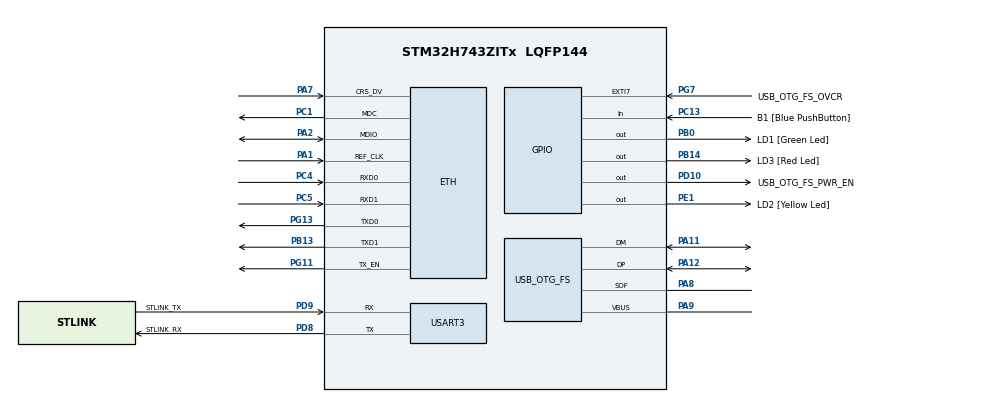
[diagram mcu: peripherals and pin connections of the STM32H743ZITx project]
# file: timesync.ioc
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Mcu.Family=STM32H7
LWIP0.BSP.STBoard=false
RCC.CortexFreq_Value=64000000
PH0-OSC_IN\ (PH0).Signal=RCC_OSC_IN
PB14.GPIO_Label=LD3 [Red Led]
PC15-OSC32_OUT\ (OSC32_OUT).Mode=LSE-External-Oscillator
RCC.PLLFRACN=0
PA11.Mode=Device_Only
PB0.GPIO_Label=LD1 [Green Led]
NVIC.TIM1_UP_IRQn=true\:0\:0\:false\:false\:true\:false\:false\:true
PC5.Mode=RMII
PC13.GPIO_Label=B1 [Blue PushButton]
PB13.Signal=ETH_TXD1
PG13.Signal=ETH_TXD0
PD9.Mode=Asynchronous
PG11.Signal=ETH_TX_EN
ProjectManager.StackSize=0x400
VP_FREERTOS_VS_CMSIS_V2.Mode=CMSIS_V2
USART3.VirtualMode-Asynchronous=VM_ASYNC
PA12.Signal=USB_OTG_FS_DP
RCC.HCLKFreq_Value=64000000
PD8.Signal=USART3_TX
PE1.Signal=GPIO_Output
NVIC.ETH_IRQn=true\:5\:0\:false\:false\:true\:true\:true\:true
RCC.HSE_VALUE=8000000
RCC.DIVM1=1
VP_SYS_VS_tim1.Mode=TIM1
PA8.Signal=USB_OTG_FS_SOF
PG13.Mode=RMII
LWIP0.BSP.solution=LAN8742
RCC.APB3Freq_Value=64000000
LWIP0.BSP.component=LAN8742
Mcu.Package=LQFP144
NVIC.TimeBase=TIM1_UP_IRQn
NVIC.TimeBaseIP=TIM1
USB_OTG_FS.VirtualMode=Device_Only
PC14-OSC32_IN\ (OSC32_IN).Mode=LSE-External-Oscillator
RCC.APB4Freq_Value=64000000
PC5.Signal=ETH_RXD1
PB13.Mode=RMII
PH0-OSC_IN\ (PH0).Mode=HSE-External-Clock-Source
PC4.Mode=RMII
RCC.DIVQ1=4
FREERTOS.Tasks01=defaultTask,24,128,StartDefaultTask,Default,NULL,Dynamic,NULL,NULL
PA7.Mode=RMII
PG7.Signal=GPXTI7
LWIP0.BSP.i2caddr=0
PD9.GPIO_Label=STLINK_TX
PC13.Signal=GPIO_Input
PC4.Signal=ETH_RXD0
RCC.D2PPRE1=RCC_APB1_DIV2
PD9.Signal=USART3_RX
LWIP.LWIP_DHCP=1
PH1-OSC_OUT\ (PH1).Signal=RCC_OSC_OUT
VP_LWIP_VS_Enabled.Mode=Enabled
PD8.GPIO_Label=STLINK_RX
PD10.Signal=GPIO_Output
PA9.Mode=Activate_VBUS
ProjectManager.TargetToolchain=STM32CubeIDE
PC15-OSC32_OUT\ (OSC32_OUT).Signal=RCC_OSC32_OUT
PA9.Signal=USB_OTG_FS_VBUS
RCC.DIVN1=24
LWIP0.BSP.instance=LAN8742
RCC.USBFreq_Value=48000000
PD10.GPIO_Label=USB_OTG_FS_PWR_EN
LWIP0.BSP.api=BSP_COMPONENT_DRIVER
PD8.Mode=Asynchronous
PA1.Signal=ETH_REF_CLK
PB14.Signal=GPIO_Output
board=NUCLEO-H743ZI2
PE1.GPIO_Label=LD2 [Yellow Led]
RCC.APB2Freq_Value=64000000
PA1.Mode=RMII
PG7.GPIO_Label=USB_OTG_FS_OVCR
RCC.ADCFreq_Value=16125000
Mcu.Name=STM32H743ZITx
PA2.Signal=ETH_MDIO
RCC.SYSCLKFreq_VALUE=64000000
ETH.MediaInterface=HAL_ETH_RMII_MODE
PA12.Mode=Device_Only
LWIP.BSP.number=1
PC14-OSC32_IN\ (OSC32_IN).Signal=RCC_OSC32_IN
PG11.Mode=RMII
PA11.Signal=USB_OTG_FS_DM
ProjectManager.HeapSize=0x200
LWIP.Version=v2.1.2_Cube
NVIC.PriorityGroup=NVIC_PRIORITYGROUP_4
PA2.Mode=RMII
PA8.Mode=Activate_SOF_FS
CORTEX_M7.CPU_DCache=Enabled
LWIP0.BSP.name=Driver_PHY
RCC.APB1Freq_Value=32000000
PB0.Signal=GPIO_Output
PC1.Signal=ETH_MDC
PC1.Mode=RMII
PA7.Signal=ETH_CRS_DV

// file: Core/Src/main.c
/* USER CODE BEGIN Header */
/**
  ******************************************************************************
  * @file           : main.c
  * @brief          : Main program body
  ******************************************************************************
  * @attention
  *
  * <h2><center>&copy; Copyright (c) 2021 STMicroelectronics.
  * All rights reserved.</center></h2>
  *
  * This software component is licensed by ST under Ultimate Liberty license
  * SLA0044, the "License"; You may not use this file except in compliance with
  * the License. You may obtain a copy of the License at:
  *                             www.st.com/SLA0044
  *
  ******************************************************************************
  */
/* USER CODE END Header */
#include "main.h"
#include "cmsis_os.h"
#include "mbedtls.h"
#include "net_sockets.h"
#include "lwip.h"
#include "ptpd.h"

UART_HandleTypeDef huart3;

PCD_HandleTypeDef hpcd_USB_OTG_FS;

/* Definitions for defaultTask */
osThreadId_t defaultTaskHandle;
const osThreadAttr_t defaultTask_attributes = {
  .name = "defaultTask",
  .priority = (osPriority_t) osPriorityNormal,
  .stack_size = 128 * 4
};

void SystemClock_Config(void);
static void MX_GPIO_Init(void);
static void MX_USART3_UART_Init(void);
static void MX_USB_OTG_FS_PCD_Init(void);
void StartDefaultTask(void *argument);

int main(void)
{

  /* Enable D-Cache---------------------------------------------------------*/
  SCB_EnableDCache();

  /* MCU Configuration--------------------------------------------------------*/

  /* Reset of all peripherals, Initializes the Flash interface and the Systick. */
  HAL_Init();

  /* Configure the system clock */
  SystemClock_Config();

  /* Initialize all configured peripherals */
  MX_GPIO_Init();
  MX_USART3_UART_Init();
  MX_USB_OTG_FS_PCD_Init();
 // MX_MBEDTLS_Init(); //Guru
  /* USER CODE BEGIN 2 */
  MX_LWIP_Init();
  /* USER CODE END 2 */

  ptpd_init();
  ptpd_task();
  ptpd_alert();

  /* Init scheduler */
  osKernelInitialize();

  /* Create the thread(s) */
  /* creation of defaultTask */
  defaultTaskHandle = osThreadNew(StartDefaultTask, NULL, &defaultTask_attributes);

  /* Start scheduler */
  osKernelStart();

  /* We should never get here as control is now taken by the scheduler */
  /* Infinite loop */
  /* USER CODE BEGIN WHILE */
  while (1)
  {
    printf("MAIN:Invalid configuration");
    assert( false );
    /* USER CODE END WHILE */

  }
}

void SystemClock_Config(void)
{
  RCC_OscInitTypeDef RCC_OscInitStruct = {0};
  RCC_ClkInitTypeDef RCC_ClkInitStruct = {0};
  RCC_PeriphCLKInitTypeDef PeriphClkInitStruct = {0};

  /** Supply configuration update enable
  */
  HAL_PWREx_ConfigSupply(PWR_LDO_SUPPLY);
  /** Configure the main internal regulator output voltage
  */
  __HAL_PWR_VOLTAGESCALING_CONFIG(PWR_REGULATOR_VOLTAGE_SCALE3);

  while(!__HAL_PWR_GET_FLAG(PWR_FLAG_VOSRDY)) {}
  /** Initializes the RCC Oscillators according to the specified parameters
  * in the RCC_OscInitTypeDef structure.
  */
  RCC_OscInitStruct.OscillatorType = RCC_OSCILLATORTYPE_HSI|RCC_OSCILLATORTYPE_HSE;
  RCC_OscInitStruct.HSEState = RCC_HSE_BYPASS;
  RCC_OscInitStruct.HSIState = RCC_HSI_DIV1;
  RCC_OscInitStruct.HSICalibrationValue = RCC_HSICALIBRATION_DEFAULT;
  RCC_OscInitStruct.PLL.PLLState = RCC_PLL_ON;
  RCC_OscInitStruct.PLL.PLLSource = RCC_PLLSOURCE_HSE;
  RCC_OscInitStruct.PLL.PLLM = 1;
  RCC_OscInitStruct.PLL.PLLN = 24;
  RCC_OscInitStruct.PLL.PLLP = 2;
  RCC_OscInitStruct.PLL.PLLQ = 4;
  RCC_OscInitStruct.PLL.PLLR = 2;
  RCC_OscInitStruct.PLL.PLLRGE = RCC_PLL1VCIRANGE_3;
  RCC_OscInitStruct.PLL.PLLVCOSEL = RCC_PLL1VCOWIDE;
  RCC_OscInitStruct.PLL.PLLFRACN = 0;
  if (HAL_RCC_OscConfig(&RCC_OscInitStruct) != HAL_OK)
  {
    Error_Handler();
  }
  /** Initializes the CPU, AHB and APB buses clocks
  */
  RCC_ClkInitStruct.ClockType = RCC_CLOCKTYPE_HCLK|RCC_CLOCKTYPE_SYSCLK
                              |RCC_CLOCKTYPE_PCLK1|RCC_CLOCKTYPE_PCLK2
                              |RCC_CLOCKTYPE_D3PCLK1|RCC_CLOCKTYPE_D1PCLK1;
  RCC_ClkInitStruct.SYSCLKSource = RCC_SYSCLKSOURCE_HSI;
  RCC_ClkInitStruct.SYSCLKDivider = RCC_SYSCLK_DIV1;
  RCC_ClkInitStruct.AHBCLKDivider = RCC_HCLK_DIV1;
  RCC_ClkInitStruct.APB3CLKDivider = RCC_APB3_DIV1;
  RCC_ClkInitStruct.APB1CLKDivider = RCC_APB1_DIV1;
  RCC_ClkInitStruct.APB2CLKDivider = RCC_APB2_DIV1;
  RCC_ClkInitStruct.APB4CLKDivider = RCC_APB4_DIV1;

  if (HAL_RCC_ClockConfig(&RCC_ClkInitStruct, FLASH_LATENCY_0) != HAL_OK)
  {
    Error_Handler();
  }
  PeriphClkInitStruct.PeriphClockSelection = RCC_PERIPHCLK_USART3|RCC_PERIPHCLK_USB;
  PeriphClkInitStruct.Usart234578ClockSelection = RCC_USART234578CLKSOURCE_D2PCLK1;
  PeriphClkInitStruct.UsbClockSelection = RCC_USBCLKSOURCE_PLL;
  if (HAL_RCCEx_PeriphCLKConfig(&PeriphClkInitStruct) != HAL_OK)
  {
    Error_Handler();
  }
  /** Enable USB Voltage detector
  */
  HAL_PWREx_EnableUSBVoltageDetector();
}

static void MX_USART3_UART_Init(void)
{

  huart3.Instance = USART3;
  huart3.Init.BaudRate = 115200;
  huart3.Init.WordLength = UART_WORDLENGTH_8B;
  huart3.Init.StopBits = UART_STOPBITS_1;
  huart3.Init.Parity = UART_PARITY_NONE;
  huart3.Init.Mode = UART_MODE_TX_RX;
  huart3.Init.HwFlowCtl = UART_HWCONTROL_NONE;
  huart3.Init.OverSampling = UART_OVERSAMPLING_16;
  huart3.Init.OneBitSampling = UART_ONE_BIT_SAMPLE_DISABLE;
  huart3.Init.ClockPrescaler = UART_PRESCALER_DIV1;
  huart3.AdvancedInit.AdvFeatureInit = UART_ADVFEATURE_NO_INIT;
  if (HAL_UART_Init(&huart3) != HAL_OK)
  {
    Error_Handler();
  }
  if (HAL_UARTEx_SetTxFifoThreshold(&huart3, UART_TXFIFO_THRESHOLD_1_8) != HAL_OK)
  {
    Error_Handler();
  }
  if (HAL_UARTEx_SetRxFifoThreshold(&huart3, UART_RXFIFO_THRESHOLD_1_8) != HAL_OK)
  {
    Error_Handler();
  }
  if (HAL_UARTEx_DisableFifoMode(&huart3) != HAL_OK)
  {
    Error_Handler();
  }
  /* USER CODE BEGIN USART3_Init 2 */
  printf ("PTP Timesynchronization application\r\n");
  /* USER CODE END USART3_Init 2 */

}

static void MX_USB_OTG_FS_PCD_Init(void)
{

  hpcd_USB_OTG_FS.Instance = USB_OTG_FS;
  hpcd_USB_OTG_FS.Init.dev_endpoints = 9;
  hpcd_USB_OTG_FS.Init.speed = PCD_SPEED_FULL;
  hpcd_USB_OTG_FS.Init.dma_enable = DISABLE;
  hpcd_USB_OTG_FS.Init.phy_itface = PCD_PHY_EMBEDDED;
  hpcd_USB_OTG_FS.Init.Sof_enable = ENABLE;
  hpcd_USB_OTG_FS.Init.low_power_enable = DISABLE;
  hpcd_USB_OTG_FS.Init.lpm_enable = DISABLE;
  hpcd_USB_OTG_FS.Init.battery_charging_enable = ENABLE;
  hpcd_USB_OTG_FS.Init.vbus_sensing_enable = ENABLE;
  hpcd_USB_OTG_FS.Init.use_dedicated_ep1 = DISABLE;
  if (HAL_PCD_Init(&hpcd_USB_OTG_FS) != HAL_OK)
  {
    Error_Handler();
  }

}

static void MX_GPIO_Init(void)
{
  GPIO_InitTypeDef GPIO_InitStruct = {0};

  /* GPIO Ports Clock Enable */
  __HAL_RCC_GPIOC_CLK_ENABLE();
  __HAL_RCC_GPIOH_CLK_ENABLE();
  __HAL_RCC_GPIOA_CLK_ENABLE();
  __HAL_RCC_GPIOB_CLK_ENABLE();
  __HAL_RCC_GPIOD_CLK_ENABLE();
  __HAL_RCC_GPIOG_CLK_ENABLE();
  __HAL_RCC_GPIOE_CLK_ENABLE();

  /*Configure GPIO pin Output Level */
  HAL_GPIO_WritePin(GPIOB, LD1_Pin|LD3_Pin, GPIO_PIN_RESET);

  /*Configure GPIO pin Output Level */
  HAL_GPIO_WritePin(USB_OTG_FS_PWR_EN_GPIO_Port, USB_OTG_FS_PWR_EN_Pin, GPIO_PIN_RESET);

  /*Configure GPIO pin Output Level */
  HAL_GPIO_WritePin(LD2_GPIO_Port, LD2_Pin, GPIO_PIN_RESET);

  /*Configure GPIO pin : B1_Pin */
  GPIO_InitStruct.Pin = B1_Pin;
  GPIO_InitStruct.Mode = GPIO_MODE_INPUT;
  GPIO_InitStruct.Pull = GPIO_NOPULL;
  HAL_GPIO_Init(B1_GPIO_Port, &GPIO_InitStruct);

  /*Configure GPIO pins : LD1_Pin LD3_Pin */
  GPIO_InitStruct.Pin = LD1_Pin|LD3_Pin;
  GPIO_InitStruct.Mode = GPIO_MODE_OUTPUT_PP;
  GPIO_InitStruct.Pull = GPIO_NOPULL;
  GPIO_InitStruct.Speed = GPIO_SPEED_FREQ_LOW;
  HAL_GPIO_Init(GPIOB, &GPIO_InitStruct);

  /*Configure GPIO pin : USB_OTG_FS_PWR_EN_Pin */
  GPIO_InitStruct.Pin = USB_OTG_FS_PWR_EN_Pin;
  GPIO_InitStruct.Mode = GPIO_MODE_OUTPUT_PP;
  GPIO_InitStruct.Pull = GPIO_NOPULL;
  GPIO_InitStruct.Speed = GPIO_SPEED_FREQ_LOW;
  HAL_GPIO_Init(USB_OTG_FS_PWR_EN_GPIO_Port, &GPIO_InitStruct);

  /*Configure GPIO pin : USB_OTG_FS_OVCR_Pin */
  GPIO_InitStruct.Pin = USB_OTG_FS_OVCR_Pin;
  GPIO_InitStruct.Mode = GPIO_MODE_IT_RISING;
  GPIO_InitStruct.Pull = GPIO_NOPULL;
  HAL_GPIO_Init(USB_OTG_FS_OVCR_GPIO_Port, &GPIO_InitStruct);

  /*Configure GPIO pin : LD2_Pin */
  GPIO_InitStruct.Pin = LD2_Pin;
  GPIO_InitStruct.Mode = GPIO_MODE_OUTPUT_PP;
  GPIO_InitStruct.Pull = GPIO_NOPULL;
  GPIO_InitStruct.Speed = GPIO_SPEED_FREQ_LOW;
  HAL_GPIO_Init(LD2_GPIO_Port, &GPIO_InitStruct);

}

void StartDefaultTask(void *argument)
{

  /* USER CODE BEGIN 5 */
 //	mbedtls_net_context mbedtls_context;
 // mbedtls_net_init(&mbedtls_context);
  //MX_LWIP_Init();
  /* Infinite loop */

  for(;;)
  {
	  HAL_GPIO_TogglePin(LD3_GPIO_Port, LD3_Pin);
	  osDelay(250);
  }
  /* USER CODE END 5 */
}

void HAL_TIM_PeriodElapsedCallback(TIM_HandleTypeDef *htim)
{
  if (htim->Instance == TIM1) {
    HAL_IncTick();
  }
}

void Error_Handler(void)
{
}

int __io_putchar (int ch) {
  HAL_StatusTypeDef hstatus;
  hstatus = HAL_UART_Transmit(&huart3, &ch, 1, HAL_MAX_DELAY);
  if (hstatus == HAL_OK)
    return 1;
  else
    return -1;
}

/************************ (C) COPYRIGHT STMicroelectronics *****END OF FILE****/
